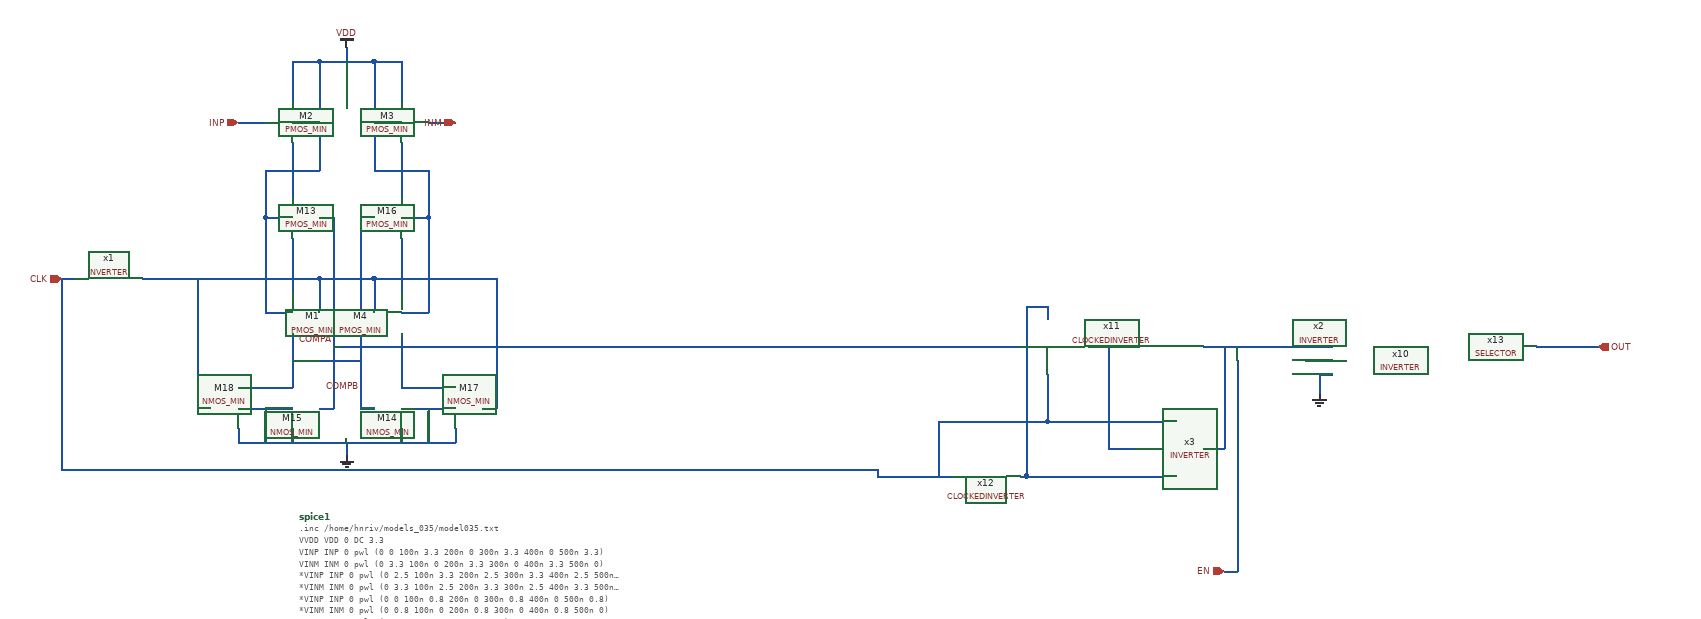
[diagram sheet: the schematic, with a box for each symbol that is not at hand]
v {xschem version=3.4.7RC file_version=1.2}
G {}
K {}
V {}
S {}
E {}
N 820 -60 890 -60 {lab=CLK}
N 820 -240 880 -240 {lab=COMPA}
N 100 -120 100 -100 {lab=GND}
N 100 -100 420 -100 {lab=GND}
N 420 -120 420 -100 {lab=GND}
N 340 -120 340 -100 {lab=GND}
N 180 -120 180 -100 {lab=GND}
N 260 -100 260 -80 {lab=GND}
N 100 -150 180 -150 {lab=GND}
N 140 -150 140 -100 {lab=GND}
N 340 -150 420 -150 {lab=GND}
N 380 -150 380 -100 {lab=GND}
N 100 -570 140 -570 {lab=INP}
N 380 -570 420 -570 {lab=INM}
N 220 -150 240 -150 {lab=COMPA}
N 240 -430 240 -150 {lab=COMPA}
N 220 -430 240 -430 {lab=COMPA}
N 280 -430 300 -430 {lab=COMPB}
N 280 -430 280 -150 {lab=COMPB}
N 280 -150 300 -150 {lab=COMPB}
N 100 -180 180 -180 {lab=COMPB}
N 340 -180 420 -180 {lab=COMPA}
N 180 -260 180 -180 {lab=COMPB}
N 340 -260 340 -180 {lab=COMPA}
N 340 -400 340 -320 {lab=#net1}
N 180 -400 180 -320 {lab=#net2}
N 180 -540 180 -460 {lab=#net3}
N 340 -540 340 -460 {lab=#net4}
N 220 -340 220 -290 {lab=#net5}
N 60 -340 220 -340 {lab=#net5}
N 220 -340 300 -340 {lab=#net5}
N 300 -340 300 -290 {lab=#net5}
N 300 -340 480 -340 {lab=#net5}
N 460 -150 480 -150 {lab=#net5}
N 0 -340 60 -340 {lab=#net5}
N 40 -150 60 -150 {lab=#net5}
N 140 -290 180 -290 {lab=VDD}
N 340 -290 380 -290 {lab=VDD}
N 140 -430 180 -430 {lab=VDD}
N 140 -500 140 -430 {lab=VDD}
N 140 -500 220 -500 {lab=VDD}
N 220 -660 220 -500 {lab=VDD}
N 340 -430 380 -430 {lab=VDD}
N 380 -500 380 -430 {lab=VDD}
N 300 -500 380 -500 {lab=VDD}
N 300 -660 300 -500 {lab=VDD}
N 300 -570 340 -570 {lab=VDD}
N 180 -570 220 -570 {lab=VDD}
N 220 -660 300 -660 {lab=VDD}
N 260 -680 260 -660 {lab=VDD}
N 180 -660 180 -600 {lab=VDD}
N 180 -660 220 -660 {lab=VDD}
N 340 -660 340 -600 {lab=VDD}
N 300 -660 340 -660 {lab=VDD}
N 140 -430 140 -290 {lab=VDD}
N 380 -430 380 -290 {lab=VDD}
N 180 -220 280 -220 {lab=COMPB}
N 240 -240 340 -240 {lab=COMPA}
N -160 -340 -140 -340 {lab=CLK}
N -40 -340 0 -340 {lab=#net5}
N 40 -340 40 -300 {lab=#net5}
N 40 -200 40 -150 {lab=#net5}
N 480 -340 480 -300 {lab=#net5}
N 340 -240 820 -240 {lab=COMPA}
N 480 -180 480 -160 {lab=#net5}
N 480 -200 480 -180 {lab=#net5}
N 40 -300 40 -200 {lab=#net5}
N 480 -300 480 -200 {lab=#net5}
N 750 -60 820 -60 {lab=CLK}
N 480 -160 480 -150 {lab=#net5}
N -160 -340 -160 -60 {lab=CLK}
N -160 -60 750 -60 {lab=CLK}
N 1260 -50 1460 -50 {lab=#net6}
N 1580 -240 1600 -240 {lab=#net7}
N 1550 -240 1550 -140 {lab=#net7}
N 1600 -240 1620 -240 {lab=#net7}
N 1250 -50 1260 -50 {lab=#net6}
N 1290 -130 1460 -130 {lab=CLK}
N 1620 -240 1690 -240 {lab=#net7}
N 2010 -240 2100 -240 {lab=OUT}
N 1690 -200 1690 -170 {lab=GND}
N 1680 -220 1690 -220 {lab=#net8}
N 1690 -240 1710 -240 {lab=#net7}
N 1690 -220 1710 -220 {lab=#net8}
N 1690 -200 1710 -200 {lab=GND}
N 1120 -50 1150 -50 {lab=CLK}
N 1290 -300 1290 -280 {lab=#net6}
N 1260 -300 1290 -300 {lab=#net6}
N 1260 -300 1260 -100 {lab=#net6}
N 1150 -130 1290 -130 {lab=CLK}
N 1130 -130 1130 -50 {lab=CLK}
N 1130 -130 1150 -130 {lab=CLK}
N 1290 -200 1290 -180 {lab=CLK}
N 1670 -220 1680 -220 {lab=#net8}
N 1570 -220 1570 -40 {lab=EN}
N 1520 -240 1580 -240 {lab=#net7}
N 1460 -50 1480 -50 {lab=#net6}
N 1460 -130 1480 -130 {lab=CLK}
N 1350 -240 1420 -240 {lab=#net9}
N 1380 -90 1420 -90 {lab=#net9}
N 1260 -100 1260 -50 {lab=#net6}
N 1380 -150 1380 -90 {lab=#net9}
N 1290 -180 1290 -130 {lab=CLK}
N 1380 -240 1380 -150 {lab=#net9}
N 1520 -90 1550 -90 {lab=#net7}
N 1550 -140 1550 -90 {lab=#net7}
N 1570 -40 1570 90 {lab=EN}
N 1550 90 1570 90 {lab=EN}
N 880 -240 1250 -240 {lab=COMPA}
N 890 -60 1040 -60 {lab=CLK}
N 1040 -60 1040 -50 {lab=CLK}
N 1040 -50 1120 -50 {lab=CLK}
C {code_shown.sym} 190 10 0 0 {name=spice1 only_toplevel=false value="

.inc /home/hnriv/models_035/model035.txt

VVDD VDD 0 DC 3.3

VINP INP 0 pwl (0   0 100n 3.3 200n   0 300n 3.3 400n   0 500n 3.3)
VINM INM 0 pwl (0 3.3 100n   0 200n 3.3 300n   0 400n 3.3 500n 0)

*VINP INP 0 pwl (0 2.5 100n 3.3 200n 2.5 300n 3.3 400n 2.5 500n 3.3)
*VINM INM 0 pwl (0 3.3 100n 2.5 200n 3.3 300n 2.5 400n 3.3 500n 2.5)

*VINP INP 0 pwl (0   0 100n 0.8 200n   0 300n 0.8 400n   0 500n 0.8)
*VINM INM 0 pwl (0 0.8 100n   0 200n 0.8 300n   0 400n 0.8 500n 0)


VCLK CLK 0 pulse(0 3.3 25n 1n 1n 50n 100n)
ven EN 0 pulse(0 3.3 0n 1n 1n 200n 252n)

.control
tran 1n 400n

plot v(OUT)
*plot v(CLK)
*plot v(INP)
*plot v(INM)

write "clocked_comparator_p.raw"

.endc"}
C {PMOS_MIN.sym} 140 -570 0 0 {name=M2 model=pch w=10.5u l=0.35u as=0 ps=0 ad=0 pd=0 m=1}
C {PMOS_MIN.sym} 380 -570 2 0 {name=M3 model=pch w=10.5u l=0.35u as=0 ps=0 ad=0 pd=0 m=1qqq}
C {NMOS_MIN.sym} 300 -150 0 0 {name=M14 model=nch w=3.5u l=0.35u as=0 ps=0 ad=0 pd=0 m=1}
C {NMOS_MIN.sym} 220 -150 2 0 {name=M15 model=nch w=3.5u l=0.35u as=0 ps=0 ad=0 pd=0 m=1}
C {ipin.sym} 100 -570 0 0 {name=p1 lab=INP}
C {ipin.sym} 420 -570 2 0 {name=p4 lab=INM}
C {NMOS_MIN.sym} 460 -150 2 0 {name=M17 model=nch w=3.5u l=0.35u as=0 ps=0 ad=0 pd=0 m=1}
C {NMOS_MIN.sym} 60 -150 0 0 {name=M18 model=nch w=3.5u l=0.35u as=0 ps=0 ad=0 pd=0 m=1}
C {gnd.sym} 260 -80 0 0 {name=l1 lab=GND}
C {PMOS_MIN.sym} 220 -430 2 0 {name=M13 model=pch w=10.5u l=0.35u as=0 ps=0 ad=0 pd=0 m=1qqq}
C {PMOS_MIN.sym} 300 -430 0 0 {name=M16 model=pch w=10.5u l=0.35u as=0 ps=0 ad=0 pd=0 m=1}
C {vdd.sym} 260 -680 0 0 {name=l5 lab=VDD}
C {ipin.sym} -160 -340 0 0 {name=p5 lab=CLK}
C {PMOS_MIN.sym} 220 -290 2 0 {name=M1 model=pch w=10.5u l=0.35u as=0 ps=0 ad=0 pd=0 m=1qqq}
C {PMOS_MIN.sym} 300 -290 0 0 {name=M4 model=pch w=10.5u l=0.35u as=0 ps=0 ad=0 pd=0 m=1}
C {lab_wire.sym} 240 -250 0 0 {name=p6 sig_type=std_logic lab=COMPA}
C {lab_wire.sym} 280 -180 0 0 {name=p7 sig_type=std_logic lab=COMPB}
C {opin.sym} 2100 -240 0 0 {name=p8 lab=OUT}
C {ipin.sym} 1550 90 0 0 {name=p9 lab=EN}
C {gnd.sym} 1690 -170 0 0 {name=l2 lab=GND}
C {LR_Work2/symbol/INVERTER.sym} 1660 -240 0 0 {name=x2}
C {LR_Work2/symbol/INVERTER.sym} 1390 -50 0 0 {name=x3}
C {LR_Work2/symbol/INVERTER.sym} 1810 -220 0 0 {name=x10}
C {LR_Work2/symbol/CLOCKEDINVERTER.sym} 1410 -240 0 0 {name=x11}
C {LR_Work2/symbol/CLOCKEDINVERTER.sym} 1360 -90 2 0 {name=x12}
C {LR_Work2/symbol/SELECTOR.sym} 1860 -220 0 0 {name=x13}
C {LR_Work2/symbol/INVERTER.sym} 100 -340 0 0 {name=x1}
